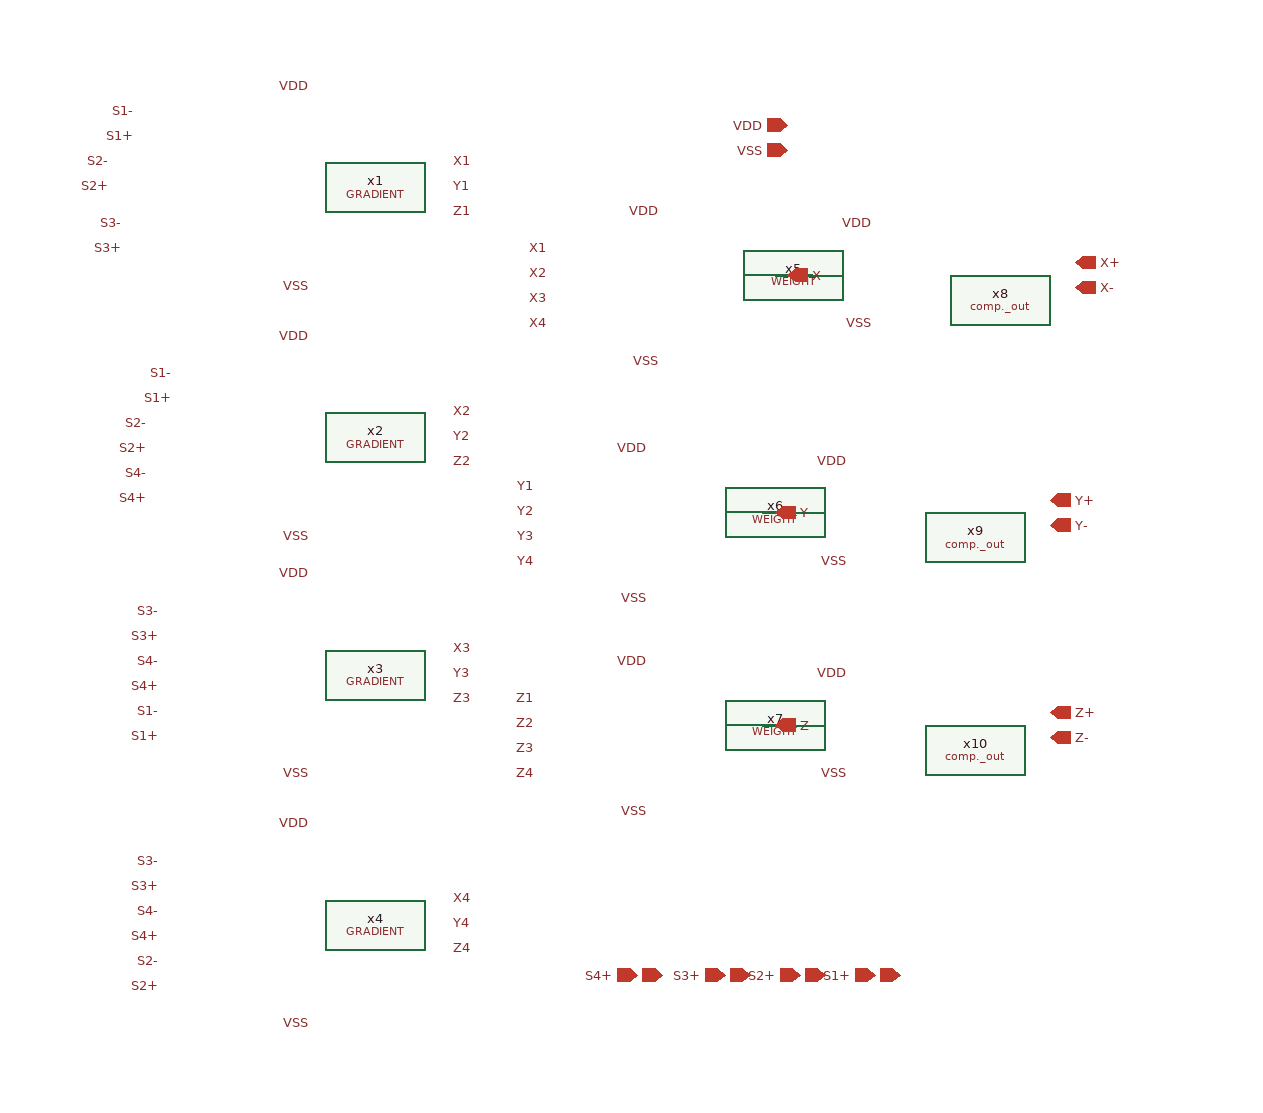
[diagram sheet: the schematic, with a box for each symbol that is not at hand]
v {xschem version=3.4.8RC file_version=1.3}
G {}
K {}
V {}
S {}
F {}
E {}
N 440 370 460 370 {lab=Z}
N 440 200 460 200 {lab=Y}
N 450 10 480 10 {lab=X}
C {DESIGN/FINAL/COMBINATION/GRADIENT.sym} 130 -60 0 0 {name=x1}
C {DESIGN/FINAL/COMBINATION/GRADIENT.sym} 130 140 0 0 {name=x2}
C {DESIGN/FINAL/COMBINATION/GRADIENT.sym} 130 330 0 0 {name=x3}
C {DESIGN/FINAL/COMBINATION/GRADIENT.sym} 130 530 0 0 {name=x4}
C {DESIGN/FINAL/WEIGTH/WEIGHT.sym} 420 30 0 0 {name=x5}
C {DESIGN/FINAL/WEIGTH/WEIGHT.sym} 410 220 0 0 {name=x6}
C {DESIGN/FINAL/WEIGTH/WEIGHT.sym} 410 390 0 0 {name=x7}
C {ipin.sym} 550 570 1 0 {name=p1 lab=S1-}
C {iopin.sym} 460 -110 0 0 {name=p2 lab=VDD}
C {opin.sym} 690 20 0 0 {name=p3 lab=X-}
C {lab_pin.sym} 80 -140 0 0 {name=p4 sig_type=std_logic lab=VDD}
C {lab_pin.sym} 80 60 0 0 {name=p5 sig_type=std_logic lab=VDD}
C {lab_pin.sym} 360 -40 0 0 {name=p6 sig_type=std_logic lab=VDD}
C {lab_pin.sym} 350 150 0 0 {name=p7 sig_type=std_logic lab=VDD}
C {lab_pin.sym} 350 320 0 0 {name=p8 sig_type=std_logic lab=VDD}
C {lab_pin.sym} 80 250 0 0 {name=p9 sig_type=std_logic lab=VDD}
C {lab_pin.sym} 80 450 0 0 {name=p10 sig_type=std_logic lab=VDD}
C {lab_pin.sym} 80 20 0 0 {name=p11 sig_type=std_logic lab=VSS}
C {lab_pin.sym} 80 220 0 0 {name=p12 sig_type=std_logic lab=VSS}
C {lab_pin.sym} 80 410 0 0 {name=p13 sig_type=std_logic lab=VSS}
C {lab_pin.sym} 350 270 0 0 {name=p14 sig_type=std_logic lab=VSS}
C {lab_pin.sym} 360 80 0 0 {name=p15 sig_type=std_logic lab=VSS}
C {lab_pin.sym} 350 440 0 0 {name=p16 sig_type=std_logic lab=VSS}
C {lab_pin.sym} 80 610 0 0 {name=p17 sig_type=std_logic lab=VSS}
C {lab_pin.sym} 190 -80 2 0 {name=p18 sig_type=std_logic lab=X1}
C {lab_pin.sym} 190 -60 2 0 {name=p19 sig_type=std_logic lab=Y1}
C {lab_pin.sym} 190 -40 2 0 {name=p20 sig_type=std_logic lab=Z1}
C {lab_pin.sym} 190 120 2 0 {name=p21 sig_type=std_logic lab=X2}
C {lab_pin.sym} 190 140 2 0 {name=p22 sig_type=std_logic lab=Y2}
C {lab_pin.sym} 190 160 2 0 {name=p23 sig_type=std_logic lab=Z2}
C {lab_pin.sym} 190 310 2 0 {name=p24 sig_type=std_logic lab=X3}
C {lab_pin.sym} 190 330 2 0 {name=p25 sig_type=std_logic lab=Y3}
C {lab_pin.sym} 190 350 2 0 {name=p26 sig_type=std_logic lab=Z3}
C {lab_pin.sym} 190 510 2 0 {name=p27 sig_type=std_logic lab=X4}
C {lab_pin.sym} 190 530 2 0 {name=p28 sig_type=std_logic lab=Y4}
C {lab_pin.sym} 190 550 2 0 {name=p29 sig_type=std_logic lab=Z4}
C {lab_pin.sym} 270 -10 0 0 {name=p30 sig_type=std_logic lab=X1}
C {lab_pin.sym} 270 10 0 0 {name=p31 sig_type=std_logic lab=X2}
C {lab_pin.sym} 270 30 0 0 {name=p32 sig_type=std_logic lab=X3}
C {lab_pin.sym} 270 50 0 0 {name=p33 sig_type=std_logic lab=X4}
C {lab_pin.sym} 260 180 0 0 {name=p34 sig_type=std_logic lab=Y1}
C {lab_pin.sym} 260 200 0 0 {name=p35 sig_type=std_logic lab=Y2}
C {lab_pin.sym} 260 220 0 0 {name=p36 sig_type=std_logic lab=Y3}
C {lab_pin.sym} 260 240 0 0 {name=p37 sig_type=std_logic lab=Y4}
C {lab_pin.sym} 260 350 0 0 {name=p38 sig_type=std_logic lab=Z1}
C {lab_pin.sym} 260 370 0 0 {name=p39 sig_type=std_logic lab=Z2}
C {lab_pin.sym} 260 390 0 0 {name=p40 sig_type=std_logic lab=Z3}
C {lab_pin.sym} 260 410 0 0 {name=p41 sig_type=std_logic lab=Z4}
C {iopin.sym} 460 -90 0 0 {name=p42 lab=VSS}
C {ipin.sym} 530 570 1 0 {name=p43 lab=S1+}
C {ipin.sym} 490 570 1 0 {name=p44 lab=S2-}
C {ipin.sym} 470 570 1 0 {name=p45 lab=S2+}
C {ipin.sym} 430 570 1 0 {name=p46 lab=S3-}
C {ipin.sym} 410 570 1 0 {name=p47 lab=S3+}
C {ipin.sym} 360 570 1 0 {name=p48 lab=S4-}
C {ipin.sym} 340 570 1 0 {name=p49 lab=S4+}
C {lab_pin.sym} -40 560 0 0 {name=p52 lab=S2-}
C {lab_pin.sym} -40 580 0 0 {name=p53 lab=S2+}
C {opin.sym} 690 0 0 0 {name=p58 lab=X+}
C {opin.sym} 670 210 0 0 {name=p59 lab=Y-}
C {opin.sym} 670 190 0 0 {name=p60 lab=Y+}
C {opin.sym} 670 380 0 0 {name=p61 lab=Z-}
C {opin.sym} 670 360 0 0 {name=p62 lab=Z+}
C {DESIGN/FINAL/WEIGTH/comp._out.sym} 630 30 0 0 {name=x8}
C {DESIGN/FINAL/WEIGTH/comp._out.sym} 610 220 0 0 {name=x9}
C {DESIGN/FINAL/WEIGTH/comp._out.sym} 610 390 0 0 {name=x10}
C {lab_pin.sym} 530 -30 0 0 {name=p63 sig_type=std_logic lab=VDD}
C {lab_pin.sym} 530 50 0 0 {name=p64 sig_type=std_logic lab=VSS}
C {lab_pin.sym} 510 160 0 0 {name=p65 sig_type=std_logic lab=VDD}
C {lab_pin.sym} 510 240 0 0 {name=p66 sig_type=std_logic lab=VSS}
C {lab_pin.sym} 510 330 0 0 {name=p67 sig_type=std_logic lab=VDD}
C {lab_pin.sym} 510 410 0 0 {name=p68 sig_type=std_logic lab=VSS}
C {opin.sym} 460 10 1 0 {name=p69 lab=X}
C {opin.sym} 450 200 1 0 {name=p70 lab=Y}
C {opin.sym} 450 370 1 0 {name=p71 lab=Z}
C {lab_pin.sym} -60 -120 0 0 {name=p72 lab=S1-}
C {lab_pin.sym} -60 -100 0 0 {name=p73 lab=S1+}
C {lab_pin.sym} -80 -80 0 0 {name=p74 lab=S2-}
C {lab_pin.sym} -80 -60 0 0 {name=p75 lab=S2+}
C {lab_pin.sym} -70 -30 0 0 {name=p76 lab=S3-}
C {lab_pin.sym} -70 -10 0 0 {name=p77 lab=S3+}
C {lab_pin.sym} -30 90 0 0 {name=p78 lab=S1-}
C {lab_pin.sym} -30 110 0 0 {name=p79 lab=S1+}
C {lab_pin.sym} -50 130 0 0 {name=p80 lab=S2-}
C {lab_pin.sym} -50 150 0 0 {name=p81 lab=S2+}
C {lab_pin.sym} -50 170 0 0 {name=p82 lab=S4-}
C {lab_pin.sym} -50 190 0 0 {name=p83 lab=S4+}
C {lab_pin.sym} -40 280 0 0 {name=p84 lab=S3-}
C {lab_pin.sym} -40 300 0 0 {name=p85 lab=S3+}
C {lab_pin.sym} -40 320 0 0 {name=p86 lab=S4-}
C {lab_pin.sym} -40 340 0 0 {name=p87 lab=S4+}
C {lab_pin.sym} -40 360 0 0 {name=p88 lab=S1-}
C {lab_pin.sym} -40 380 0 0 {name=p89 lab=S1+}
C {lab_pin.sym} -40 480 0 0 {name=p90 lab=S3-}
C {lab_pin.sym} -40 500 0 0 {name=p91 lab=S3+}
C {lab_pin.sym} -40 520 0 0 {name=p92 lab=S4-}
C {lab_pin.sym} -40 540 0 0 {name=p93 lab=S4+}
